VERSION 5.7 ;
  NOWIREEXTENSIONATPIN ON ;
  DIVIDERCHAR "/" ;
  BUSBITCHARS "[]" ;
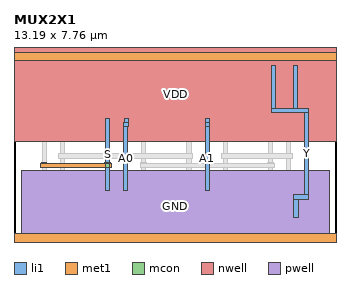
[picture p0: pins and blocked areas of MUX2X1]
MACRO MUX2X1
  CLASS CORE ;
  FOREIGN MUX2X1 ;
  ORIGIN 0.000 0.000 ;
  SIZE 13.190 BY 7.760 ;
  SYMMETRY X Y ;
  SITE unitrh ;
  PIN Y
    DIRECTION OUTPUT ;
    USE SIGNAL ;
    ANTENNADIFFAREA 1.351900 ;
    PORT
      LAYER li1 ;
        RECT 10.515 5.465 10.685 7.200 ;
        RECT 11.395 5.465 11.565 7.200 ;
        RECT 10.515 5.295 12.045 5.465 ;
        RECT 11.875 1.920 12.045 5.295 ;
        RECT 11.435 1.750 12.045 1.920 ;
        RECT 11.435 1.015 11.605 1.750 ;
    END
  END Y
  PIN A0
    DIRECTION INPUT ;
    USE SIGNAL ;
    ANTENNAGATEAREA 1.027250 ;
    PORT
      LAYER li1 ;
        RECT 4.505 4.890 4.675 5.045 ;
        RECT 4.475 4.715 4.675 4.890 ;
        RECT 4.475 2.095 4.645 4.715 ;
    END
  END A0
  PIN A1
    DIRECTION INPUT ;
    USE SIGNAL ;
    ANTENNAGATEAREA 1.027250 ;
    PORT
      LAYER li1 ;
        RECT 7.835 4.890 8.005 5.045 ;
        RECT 7.805 4.715 8.005 4.890 ;
        RECT 7.805 2.095 7.975 4.715 ;
    END
  END A1
  PIN S
    DIRECTION INPUT ;
    USE SIGNAL ;
    ANTENNAGATEAREA 2.060500 ;
    PORT
      LAYER met1 ;
        RECT 1.115 3.225 1.345 3.255 ;
        RECT 3.705 3.225 3.935 3.255 ;
        RECT 1.085 3.055 3.965 3.225 ;
        RECT 1.115 3.025 1.345 3.055 ;
        RECT 3.705 3.025 3.935 3.055 ;
    END
    PORT
      LAYER li1 ;
        RECT 3.735 2.095 3.905 5.045 ;
      LAYER mcon ;
        RECT 3.735 3.055 3.905 3.225 ;
    END
  END S
  PIN VDD
    DIRECTION INOUT ;
    USE POWER ;
    SHAPE ABUTMENT ;
    PORT
      LAYER nwell ;
        RECT 0.000 4.110 13.190 7.940 ;
      LAYER met1 ;
        RECT 0.000 7.410 13.190 7.760 ;
    END
  END VDD
  PIN GND
    DIRECTION INOUT ;
    USE GROUND ;
    SHAPE ABUTMENT ;
    PORT
      LAYER pwell ;
        RECT 0.320 0.000 12.870 2.900 ;
      LAYER met1 ;
        RECT 0.000 0.000 13.190 0.350 ;
    END
  END GND
  OBS
      LAYER li1 ;
        RECT 0.000 7.410 13.190 7.760 ;
        RECT 0.320 4.290 0.660 7.410 ;
        RECT 1.080 5.365 1.250 7.410 ;
        RECT 0.320 0.350 0.660 2.900 ;
        RECT 1.145 2.100 1.315 5.045 ;
        RECT 1.520 4.845 1.690 7.200 ;
        RECT 1.960 5.365 2.130 7.410 ;
        RECT 1.520 4.675 2.055 4.845 ;
        RECT 1.885 2.345 2.055 4.675 ;
        RECT 2.540 4.290 2.880 7.410 ;
        RECT 3.415 5.315 3.585 7.410 ;
        RECT 3.855 5.465 4.025 7.200 ;
        RECT 4.295 5.735 4.465 7.410 ;
        RECT 4.735 5.465 4.905 7.200 ;
        RECT 5.175 5.735 5.345 7.410 ;
        RECT 3.855 5.295 5.385 5.465 ;
        RECT 1.515 2.175 2.055 2.345 ;
        RECT 1.035 0.800 1.205 1.930 ;
        RECT 1.515 1.020 1.685 2.175 ;
        RECT 2.005 0.800 2.175 1.930 ;
        RECT 1.035 0.630 2.175 0.800 ;
        RECT 1.035 0.350 1.205 0.630 ;
        RECT 1.520 0.350 1.690 0.630 ;
        RECT 2.005 0.350 2.175 0.630 ;
        RECT 2.540 0.350 2.880 2.900 ;
        RECT 3.320 1.845 3.490 1.925 ;
        RECT 4.290 1.845 4.460 1.925 ;
        RECT 5.215 1.920 5.385 5.295 ;
        RECT 5.870 4.290 6.210 7.410 ;
        RECT 6.745 5.315 6.915 7.410 ;
        RECT 7.185 5.465 7.355 7.200 ;
        RECT 7.625 5.735 7.795 7.410 ;
        RECT 8.065 5.465 8.235 7.200 ;
        RECT 8.505 5.735 8.675 7.410 ;
        RECT 7.185 5.295 8.715 5.465 ;
        RECT 3.320 1.675 4.460 1.845 ;
        RECT 3.320 0.545 3.490 1.675 ;
        RECT 3.805 0.350 3.975 1.300 ;
        RECT 4.290 0.795 4.460 1.675 ;
        RECT 4.775 1.750 5.385 1.920 ;
        RECT 4.775 1.015 4.945 1.750 ;
        RECT 5.260 0.795 5.430 1.565 ;
        RECT 4.290 0.625 5.430 0.795 ;
        RECT 4.290 0.545 4.460 0.625 ;
        RECT 5.260 0.545 5.430 0.625 ;
        RECT 5.870 0.350 6.210 2.900 ;
        RECT 7.065 2.095 7.235 5.045 ;
        RECT 6.650 1.845 6.820 1.925 ;
        RECT 7.620 1.845 7.790 1.925 ;
        RECT 8.545 1.920 8.715 5.295 ;
        RECT 9.200 4.290 9.540 7.410 ;
        RECT 10.075 5.315 10.245 7.410 ;
        RECT 10.955 5.735 11.125 7.410 ;
        RECT 11.835 5.735 12.005 7.410 ;
        RECT 6.650 1.675 7.790 1.845 ;
        RECT 6.650 0.545 6.820 1.675 ;
        RECT 7.135 0.350 7.305 1.300 ;
        RECT 7.620 0.795 7.790 1.675 ;
        RECT 8.105 1.750 8.715 1.920 ;
        RECT 8.105 1.015 8.275 1.750 ;
        RECT 8.590 0.795 8.760 1.565 ;
        RECT 7.620 0.625 8.760 0.795 ;
        RECT 7.620 0.545 7.790 0.625 ;
        RECT 8.590 0.545 8.760 0.625 ;
        RECT 9.200 0.350 9.540 2.900 ;
        RECT 10.395 2.095 10.565 5.045 ;
        RECT 11.165 4.890 11.335 5.045 ;
        RECT 11.135 4.715 11.335 4.890 ;
        RECT 11.135 2.095 11.305 4.715 ;
        RECT 12.530 4.290 12.870 7.410 ;
        RECT 9.980 1.845 10.150 1.925 ;
        RECT 10.950 1.845 11.120 1.925 ;
        RECT 9.980 1.675 11.120 1.845 ;
        RECT 9.980 0.545 10.150 1.675 ;
        RECT 10.465 0.350 10.635 1.300 ;
        RECT 10.950 0.795 11.120 1.675 ;
        RECT 11.920 0.795 12.090 1.565 ;
        RECT 10.950 0.625 12.090 0.795 ;
        RECT 10.950 0.545 11.120 0.625 ;
        RECT 11.920 0.545 12.090 0.625 ;
        RECT 12.530 0.350 12.870 2.900 ;
        RECT 0.000 0.000 13.190 0.350 ;
      LAYER mcon ;
        RECT 0.775 7.495 0.945 7.665 ;
        RECT 1.145 7.495 1.315 7.665 ;
        RECT 1.515 7.495 1.685 7.665 ;
        RECT 1.885 7.495 2.055 7.665 ;
        RECT 2.255 7.495 2.425 7.665 ;
        RECT 2.995 7.495 3.165 7.665 ;
        RECT 3.365 7.495 3.535 7.665 ;
        RECT 3.735 7.495 3.905 7.665 ;
        RECT 4.105 7.495 4.275 7.665 ;
        RECT 4.475 7.495 4.645 7.665 ;
        RECT 4.845 7.495 5.015 7.665 ;
        RECT 5.215 7.495 5.385 7.665 ;
        RECT 5.585 7.495 5.755 7.665 ;
        RECT 6.325 7.495 6.495 7.665 ;
        RECT 6.695 7.495 6.865 7.665 ;
        RECT 7.065 7.495 7.235 7.665 ;
        RECT 7.435 7.495 7.605 7.665 ;
        RECT 7.805 7.495 7.975 7.665 ;
        RECT 8.175 7.495 8.345 7.665 ;
        RECT 8.545 7.495 8.715 7.665 ;
        RECT 8.915 7.495 9.085 7.665 ;
        RECT 9.655 7.495 9.825 7.665 ;
        RECT 10.025 7.495 10.195 7.665 ;
        RECT 10.395 7.495 10.565 7.665 ;
        RECT 10.765 7.495 10.935 7.665 ;
        RECT 11.135 7.495 11.305 7.665 ;
        RECT 11.505 7.495 11.675 7.665 ;
        RECT 11.875 7.495 12.045 7.665 ;
        RECT 12.245 7.495 12.415 7.665 ;
        RECT 1.145 3.055 1.315 3.225 ;
        RECT 1.885 3.425 2.055 3.595 ;
        RECT 5.215 3.055 5.385 3.225 ;
        RECT 7.065 3.425 7.235 3.595 ;
        RECT 8.545 3.425 8.715 3.595 ;
        RECT 10.395 3.055 10.565 3.225 ;
        RECT 11.135 3.425 11.305 3.595 ;
        RECT 0.775 0.095 0.945 0.265 ;
        RECT 1.145 0.095 1.315 0.265 ;
        RECT 1.515 0.095 1.685 0.265 ;
        RECT 1.885 0.095 2.055 0.265 ;
        RECT 2.255 0.095 2.425 0.265 ;
        RECT 2.995 0.095 3.165 0.265 ;
        RECT 3.365 0.095 3.535 0.265 ;
        RECT 3.735 0.095 3.905 0.265 ;
        RECT 4.105 0.095 4.275 0.265 ;
        RECT 4.475 0.095 4.645 0.265 ;
        RECT 4.845 0.095 5.015 0.265 ;
        RECT 5.215 0.095 5.385 0.265 ;
        RECT 5.585 0.095 5.755 0.265 ;
        RECT 6.325 0.095 6.495 0.265 ;
        RECT 6.695 0.095 6.865 0.265 ;
        RECT 7.065 0.095 7.235 0.265 ;
        RECT 7.435 0.095 7.605 0.265 ;
        RECT 7.805 0.095 7.975 0.265 ;
        RECT 8.175 0.095 8.345 0.265 ;
        RECT 8.545 0.095 8.715 0.265 ;
        RECT 8.915 0.095 9.085 0.265 ;
        RECT 9.655 0.095 9.825 0.265 ;
        RECT 10.025 0.095 10.195 0.265 ;
        RECT 10.395 0.095 10.565 0.265 ;
        RECT 10.765 0.095 10.935 0.265 ;
        RECT 11.135 0.095 11.305 0.265 ;
        RECT 11.505 0.095 11.675 0.265 ;
        RECT 11.875 0.095 12.045 0.265 ;
        RECT 12.245 0.095 12.415 0.265 ;
      LAYER met1 ;
        RECT 1.855 3.595 2.085 3.625 ;
        RECT 7.035 3.595 7.265 3.625 ;
        RECT 8.515 3.595 8.745 3.625 ;
        RECT 11.105 3.595 11.335 3.625 ;
        RECT 1.825 3.425 7.295 3.595 ;
        RECT 8.485 3.425 11.365 3.595 ;
        RECT 1.855 3.395 2.085 3.425 ;
        RECT 7.035 3.395 7.265 3.425 ;
        RECT 8.515 3.395 8.745 3.425 ;
        RECT 11.105 3.395 11.335 3.425 ;
        RECT 5.185 3.225 5.415 3.255 ;
        RECT 10.365 3.225 10.595 3.255 ;
        RECT 5.155 3.055 10.625 3.225 ;
        RECT 5.185 3.025 5.415 3.055 ;
        RECT 10.365 3.025 10.595 3.055 ;
  END
END MUX2X1
END LIBRARY

